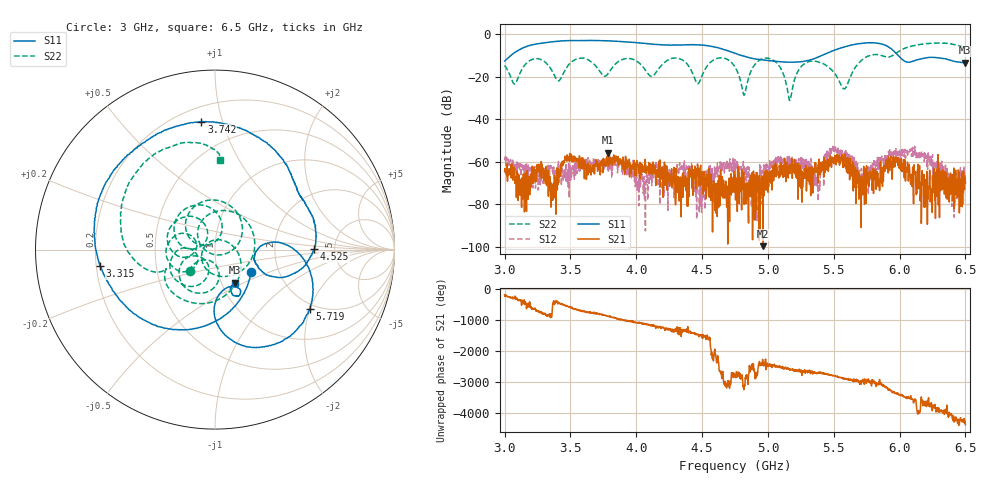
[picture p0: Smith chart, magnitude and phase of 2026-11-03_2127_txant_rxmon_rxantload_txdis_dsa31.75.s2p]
! HEWLETT PACKARD,8720ES,MY41003347,7.72, via bringup/vna_tests.py
! txant_rxmon_rxantload_txdis_dsa31.75
! measured 2026-11-03 21:28:49, 1601 points, 3000000000-6500000000 Hz, IF bandwidth 1000 Hz, source -40.00 dBm, kit CALK35MD
! board A, DSA 31.75 dB (set before each sweep)
! board A, CTRL bits {'tx_dis': 1} set before each sweep
# HZ S RI R 50
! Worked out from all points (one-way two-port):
!   1601 points, 3 GHz to 6.5 GHz, reference 50 ohm
!   highest |S21| = -55.78 dB at 3.783 GHz (marker M1); lowest = -99.8 dB at 4.962 GHz (marker M2)
!   lowest |S11| = -13.3 dB at 6.498 GHz (marker M3), VSWR 1.55, Z = 57.8 - j22.4 ohm
!   |S11| at or under -10 dB: start of sweep to 3.045 GHz; 4.803 GHz to 5.406 GHz (602.4 MHz wide, 11.8 % of centre); 5.991 GHz to end of sweep
!   |S22| runs from -31.1 to -4.0 dB; largest |S21 - S12| = 0.0026
!   S11 on the Smith chart (normalised r, x): 3 GHz: 1.44, -0.39; 3.315 GHz: 0.22, -0.07; 3.742 GHz: 0.29, +0.86; 4.525 GHz: 3.47, +0.01; 5.719 GHz: 1.85, -1.99; 6.5 GHz: 1.16, -0.45
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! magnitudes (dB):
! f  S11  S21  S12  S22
! 3 GHz  -12.5  -64.6  -58.1  -14.6
! 3.077 GHz  -8.6  -62.8  -60.9  -23.3
! 3.315 GHz  -3.8  -63.2  -64.5  -13.4
! 3.409 GHz  -3.2  -69.8  -59.9  -21.9
! 3.584 GHz  -2.9  -61.4  -61.4  -11.1
! 3.742 GHz  -2.9  -59.1  -64.9  -18.9
! 3.783 GHz  -3.0  -55.8  -62.7  -18.7
! 4.07 GHz  -4.2  -61.1  -92.6  -16.9
! 4.168 GHz  -4.8  -66.4  -61.7  -16.4
! 4.525 GHz  -5.2  -73.7  -65.7  -16.2
! 4.75 GHz  -8.9  -72.7  -69.0  -15.3
! 4.82 GHz  -10.3  -80.1  -72.6  -28.6
! 4.962 GHz  -12.0  -99.8  -72.0  -11.4
! 5.166 GHz  -13.1  -61.4  -63.8  -31.1
! 5.334 GHz  -11.8  -67.2  -62.0  -12.5
! 5.52 GHz  -7.1  -59.5  -55.6  -19.5
! 5.586 GHz  -5.8  -56.4  -55.4  -25.5
! 5.719 GHz  -4.1  -74.2  -69.4  -11.8
! 5.918 GHz  -6.0  -61.7  -56.1  -10.6
! 6.205 GHz  -11.0  -73.0  -60.0  -4.3
! 6.498 GHz  -13.3  -67.3  -66.3  -6.0
! 6.5 GHz  -13.3  -70.1  -69.9  -6.0
